One B-rep face of a CAD part: STEP entity #41862.
In plain terms, the planar face has unit normal (0, 0, 1).
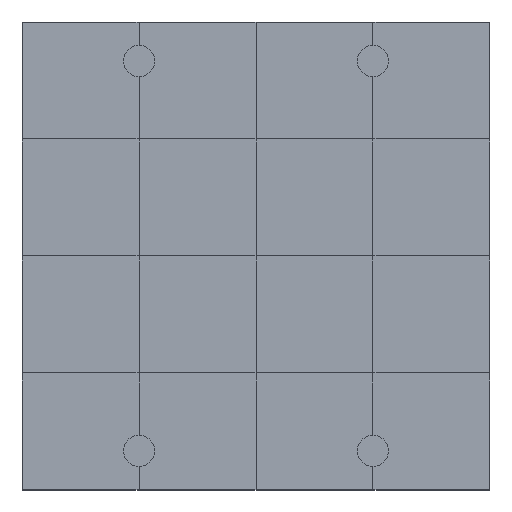
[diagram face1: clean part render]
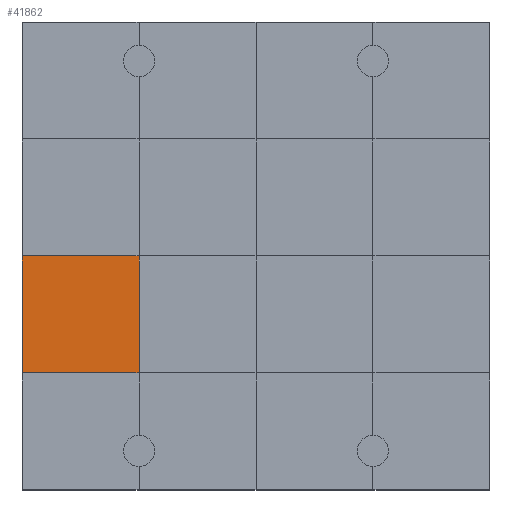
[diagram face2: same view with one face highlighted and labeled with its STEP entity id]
Its self-contained STEP definition (entity closure, numbers rounded to 3 decimals):
#41412 = VERTEX_POINT('',#41413);
#41413 = CARTESIAN_POINT('',(0.,3.,1.2));
#41427 = PLANE('',#41428);
#41428 = AXIS2_PLACEMENT_3D('',#41429,#41430,#41431);
#41429 = CARTESIAN_POINT('',(0.,3.,0.));
#41430 = DIRECTION('',(1.,0.,-0.));
#41431 = DIRECTION('',(0.,0.,1.));
#41453 = PLANE('',#41454);
#41454 = AXIS2_PLACEMENT_3D('',#41455,#41456,#41457);
#41455 = CARTESIAN_POINT('',(0.,0.,1.2));
#41456 = DIRECTION('',(0.,0.,1.));
#41457 = DIRECTION('',(1.,0.,-0.));
#41604 = VERTEX_POINT('',#41605);
#41605 = CARTESIAN_POINT('',(3.,3.,1.2));
#41626 = EDGE_CURVE('',#41412,#41604,#41627,.T.);
#41627 = SURFACE_CURVE('',#41628,(#41632,#41639),.PCURVE_S1.);
#41628 = LINE('',#41629,#41630);
#41629 = CARTESIAN_POINT('',(0.,3.,1.2));
#41630 = VECTOR('',#41631,1.);
#41631 = DIRECTION('',(1.,0.,-0.));
#41632 = PCURVE('',#41453,#41633);
#41633 = DEFINITIONAL_REPRESENTATION('',(#41634),#41638);
#41634 = LINE('',#41635,#41636);
#41635 = CARTESIAN_POINT('',(0.,3.));
#41636 = VECTOR('',#41637,1.);
#41637 = DIRECTION('',(1.,0.));
#41638 = ( GEOMETRIC_REPRESENTATION_CONTEXT(2) 
PARAMETRIC_REPRESENTATION_CONTEXT() REPRESENTATION_CONTEXT('2D SPACE',''
  ) );
#41639 = PCURVE('',#41640,#41645);
#41640 = PLANE('',#41641);
#41641 = AXIS2_PLACEMENT_3D('',#41642,#41643,#41644);
#41642 = CARTESIAN_POINT('',(0.,3.,1.2));
#41643 = DIRECTION('',(0.,0.,1.));
#41644 = DIRECTION('',(1.,0.,-0.));
#41645 = DEFINITIONAL_REPRESENTATION('',(#41646),#41650);
#41646 = LINE('',#41647,#41648);
#41647 = CARTESIAN_POINT('',(0.,0.));
#41648 = VECTOR('',#41649,1.);
#41649 = DIRECTION('',(1.,0.));
#41650 = ( GEOMETRIC_REPRESENTATION_CONTEXT(2) 
PARAMETRIC_REPRESENTATION_CONTEXT() REPRESENTATION_CONTEXT('2D SPACE',''
  ) );
#41685 = VERTEX_POINT('',#41686);
#41686 = CARTESIAN_POINT('',(0.,6.,1.2));
#41712 = EDGE_CURVE('',#41412,#41685,#41713,.T.);
#41713 = SURFACE_CURVE('',#41714,(#41718,#41725),.PCURVE_S1.);
#41714 = LINE('',#41715,#41716);
#41715 = CARTESIAN_POINT('',(0.,3.,1.2));
#41716 = VECTOR('',#41717,1.);
#41717 = DIRECTION('',(-0.,1.,0.));
#41718 = PCURVE('',#41427,#41719);
#41719 = DEFINITIONAL_REPRESENTATION('',(#41720),#41724);
#41720 = LINE('',#41721,#41722);
#41721 = CARTESIAN_POINT('',(1.2,0.));
#41722 = VECTOR('',#41723,1.);
#41723 = DIRECTION('',(0.,-1.));
#41724 = ( GEOMETRIC_REPRESENTATION_CONTEXT(2) 
PARAMETRIC_REPRESENTATION_CONTEXT() REPRESENTATION_CONTEXT('2D SPACE',''
  ) );
#41725 = PCURVE('',#41640,#41726);
#41726 = DEFINITIONAL_REPRESENTATION('',(#41727),#41731);
#41727 = LINE('',#41728,#41729);
#41728 = CARTESIAN_POINT('',(0.,0.));
#41729 = VECTOR('',#41730,1.);
#41730 = DIRECTION('',(0.,1.));
#41731 = ( GEOMETRIC_REPRESENTATION_CONTEXT(2) 
PARAMETRIC_REPRESENTATION_CONTEXT() REPRESENTATION_CONTEXT('2D SPACE',''
  ) );
#41862 = ADVANCED_FACE('',(#41863),#41640,.T.);
#41863 = FACE_BOUND('',#41864,.T.);
#41864 = EDGE_LOOP('',(#41865,#41866,#41867,#41895));
#41865 = ORIENTED_EDGE('',*,*,#41712,.F.);
#41866 = ORIENTED_EDGE('',*,*,#41626,.T.);
#41867 = ORIENTED_EDGE('',*,*,#41868,.T.);
#41868 = EDGE_CURVE('',#41604,#41869,#41871,.T.);
#41869 = VERTEX_POINT('',#41870);
#41870 = CARTESIAN_POINT('',(3.,6.,1.2));
#41871 = SURFACE_CURVE('',#41872,(#41876,#41883),.PCURVE_S1.);
#41872 = LINE('',#41873,#41874);
#41873 = CARTESIAN_POINT('',(3.,3.,1.2));
#41874 = VECTOR('',#41875,1.);
#41875 = DIRECTION('',(-0.,1.,0.));
#41876 = PCURVE('',#41640,#41877);
#41877 = DEFINITIONAL_REPRESENTATION('',(#41878),#41882);
#41878 = LINE('',#41879,#41880);
#41879 = CARTESIAN_POINT('',(3.,0.));
#41880 = VECTOR('',#41881,1.);
#41881 = DIRECTION('',(0.,1.));
#41882 = ( GEOMETRIC_REPRESENTATION_CONTEXT(2) 
PARAMETRIC_REPRESENTATION_CONTEXT() REPRESENTATION_CONTEXT('2D SPACE',''
  ) );
#41883 = PCURVE('',#41884,#41889);
#41884 = PLANE('',#41885);
#41885 = AXIS2_PLACEMENT_3D('',#41886,#41887,#41888);
#41886 = CARTESIAN_POINT('',(3.,3.,1.2));
#41887 = DIRECTION('',(0.,0.,1.));
#41888 = DIRECTION('',(1.,0.,-0.));
#41889 = DEFINITIONAL_REPRESENTATION('',(#41890),#41894);
#41890 = LINE('',#41891,#41892);
#41891 = CARTESIAN_POINT('',(0.,0.));
#41892 = VECTOR('',#41893,1.);
#41893 = DIRECTION('',(0.,1.));
#41894 = ( GEOMETRIC_REPRESENTATION_CONTEXT(2) 
PARAMETRIC_REPRESENTATION_CONTEXT() REPRESENTATION_CONTEXT('2D SPACE',''
  ) );
#41895 = ORIENTED_EDGE('',*,*,#41896,.F.);
#41896 = EDGE_CURVE('',#41685,#41869,#41897,.T.);
#41897 = SURFACE_CURVE('',#41898,(#41902,#41909),.PCURVE_S1.);
#41898 = LINE('',#41899,#41900);
#41899 = CARTESIAN_POINT('',(0.,6.,1.2));
#41900 = VECTOR('',#41901,1.);
#41901 = DIRECTION('',(1.,0.,-0.));
#41902 = PCURVE('',#41640,#41903);
#41903 = DEFINITIONAL_REPRESENTATION('',(#41904),#41908);
#41904 = LINE('',#41905,#41906);
#41905 = CARTESIAN_POINT('',(0.,3.));
#41906 = VECTOR('',#41907,1.);
#41907 = DIRECTION('',(1.,0.));
#41908 = ( GEOMETRIC_REPRESENTATION_CONTEXT(2) 
PARAMETRIC_REPRESENTATION_CONTEXT() REPRESENTATION_CONTEXT('2D SPACE',''
  ) );
#41909 = PCURVE('',#41910,#41915);
#41910 = PLANE('',#41911);
#41911 = AXIS2_PLACEMENT_3D('',#41912,#41913,#41914);
#41912 = CARTESIAN_POINT('',(0.,6.,1.2));
#41913 = DIRECTION('',(0.,0.,1.));
#41914 = DIRECTION('',(1.,0.,-0.));
#41915 = DEFINITIONAL_REPRESENTATION('',(#41916),#41920);
#41916 = LINE('',#41917,#41918);
#41917 = CARTESIAN_POINT('',(0.,0.));
#41918 = VECTOR('',#41919,1.);
#41919 = DIRECTION('',(1.,0.));
#41920 = ( GEOMETRIC_REPRESENTATION_CONTEXT(2) 
PARAMETRIC_REPRESENTATION_CONTEXT() REPRESENTATION_CONTEXT('2D SPACE',''
  ) );
